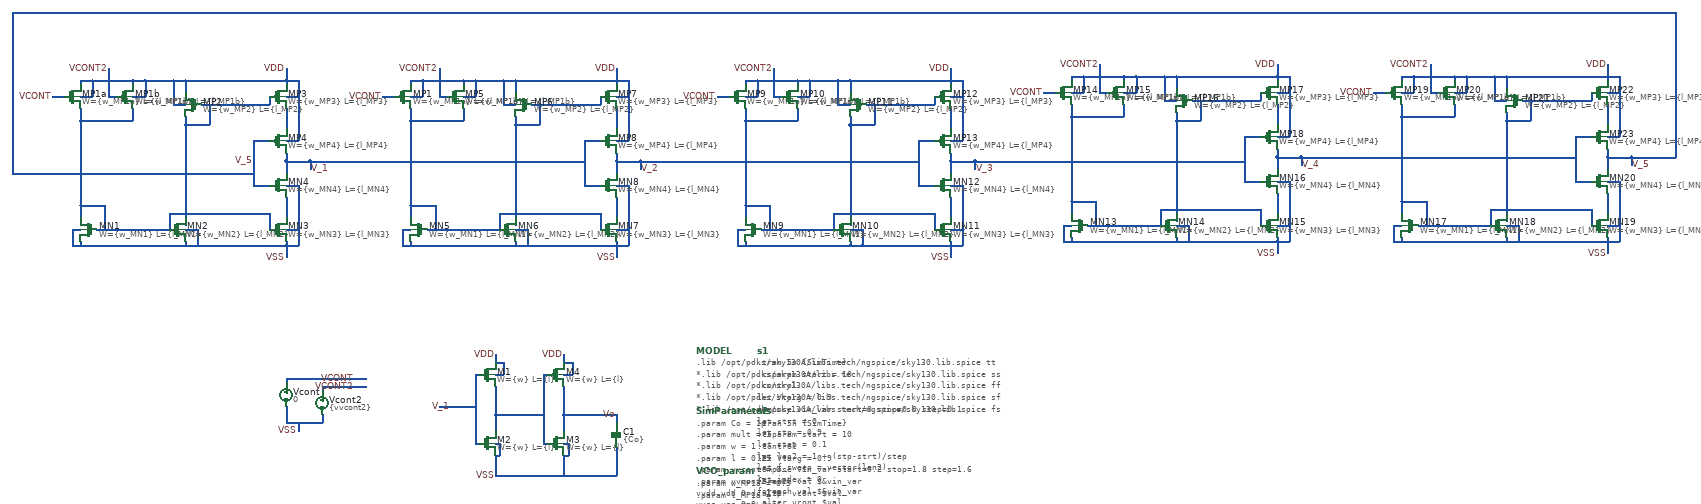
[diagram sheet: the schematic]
v {xschem version=3.4.5 file_version=1.2
}
G {}
K {}
V {}
S {}
E {}
N -2160 -960 -2160 -930 {
lab=VDD}
N -2160 -520 -2160 -490 {
lab=VSS}
N -1990 -190 -1960 -190 {
lab=VCONT}
N -1780 -120 -1750 -120 {
lab=V_1}
N -1640 -100 -1640 -60 {
lab=#net1}
N -1640 -170 -1640 -100 {
lab=#net1}
N -1640 -30 -1630 -30 {
lab=VSS}
N -1630 -30 -1630 0 {
lab=VSS}
N -1640 0 -1630 0 {
lab=VSS}
N -1640 -200 -1620 -200 {
lab=VDD}
N -1620 -230 -1620 -200 {
lab=VDD}
N -1640 -230 -1620 -230 {
lab=VDD}
N -1640 -100 -1630 -100 {
lab=#net1}
N -1690 -200 -1680 -200 {
lab=V_1}
N -1690 -200 -1690 -30 {
lab=V_1}
N -1690 -30 -1680 -30 {
lab=V_1}
N -1640 0 -1640 50 {
lab=VSS}
N -1640 -250 -1640 -230 {
lab=VDD}
N -1340 -20 -1340 50 {
lab=VSS}
N -1750 -120 -1720 -120 {
lab=V_1}
N -1340 -100 -1340 -80 {
lab=Vo}
N -1720 -120 -1690 -120 {
lab=V_1}
N -1470 -100 -1470 -60 {
lab=Vo}
N -1470 -170 -1470 -100 {
lab=Vo}
N -1470 -30 -1460 -30 {
lab=VSS}
N -1460 -30 -1460 0 {
lab=VSS}
N -1470 0 -1460 0 {
lab=VSS}
N -1470 -200 -1450 -200 {
lab=VDD}
N -1450 -230 -1450 -200 {
lab=VDD}
N -1470 -230 -1450 -230 {
lab=VDD}
N -1470 -100 -1460 -100 {
lab=Vo}
N -1520 -200 -1510 -200 {
lab=#net1}
N -1520 -200 -1520 -30 {
lab=#net1}
N -1520 -30 -1510 -30 {
lab=#net1}
N -1470 0 -1470 50 {
lab=VSS}
N -1470 -250 -1470 -230 {
lab=VDD}
N -1630 -100 -1520 -100 {
lab=#net1}
N -1470 -100 -1340 -100 {
lab=Vo}
N -1640 50 -1340 50 {
lab=VSS}
N -1990 -170 -1960 -170 {
lab=VCONT2}
N -2160 -190 -1990 -190 {
lab=VCONT}
N -2160 -190 -2160 -180 {
lab=VCONT}
N -2070 -170 -1990 -170 {
lab=VCONT2}
N -2070 -170 -2070 -160 {
lab=VCONT2}
N -2070 -100 -2070 -80 {
lab=VSS}
N -2160 -80 -2070 -80 {
lab=VSS}
N -2160 -120 -2160 -80 {
lab=VSS}
N -2130 -80 -2130 -60 {
lab=VSS}
N -2240 -780 -2200 -780 { lab=V_5}
N -2240 -780 -2240 -670 { lab=V_5}
N -2240 -670 -2200 -670 { lab=V_5}
N -2160 -730 -2160 -700 { lab=V_1}
N -2160 -860 -2160 -810 { lab=#net2}
N -2160 -780 -2130 -780 { lab=VDD}
N -2160 -670 -2130 -670 { lab=VSS}
N -2130 -670 -2130 -560 { lab=VSS}
N -2160 -640 -2160 -590 { lab=#net3}
N -2160 -730 -2100 -730 { lab=V_1}
N -2160 -520 -2160 -510 {
lab=VSS}
N -2160 -930 -2160 -920 {
lab=VDD}
N -2160 -930 -2130 -930 {
lab=VDD}
N -2130 -890 -2130 -780 {
lab=VDD}
N -2160 -890 -2130 -890 {
lab=VDD}
N -2160 -520 -2130 -520 {
lab=VSS}
N -2130 -560 -2130 -520 {
lab=VSS}
N -2160 -560 -2130 -560 {
lab=VSS}
N -2350 -870 -2200 -870 {
lab=#net4}
N -2410 -910 -2410 -900 {
lab=VDD}
N -2410 -930 -2160 -930 {
lab=VDD}
N -2410 -820 -2410 -570 {
lab=#net4}
N -2380 -520 -2160 -520 {
lab=VSS}
N -2410 -530 -2410 -520 {
lab=VSS}
N -2610 -560 -2450 -560 {
lab=#net5}
N -2670 -520 -2410 -520 {
lab=VSS}
N -2670 -530 -2670 -520 {
lab=VSS}
N -2670 -620 -2670 -590 {
lab=#net5}
N -2440 -930 -2410 -930 {
lab=VDD}
N -2670 -930 -2670 -920 {
lab=VDD}
N -2610 -620 -2610 -560 {
lab=#net5}
N -2670 -620 -2610 -620 {
lab=#net5}
N -2410 -820 -2350 -820 {
lab=#net4}
N -2350 -870 -2350 -820 {
lab=#net4}
N -2740 -890 -2710 -890 {
lab=VCONT}
N -2410 -560 -2380 -560 {
lab=VSS}
N -2380 -560 -2380 -520 {
lab=VSS}
N -2450 -600 -2450 -560 {
lab=#net5}
N -2450 -600 -2200 -600 {
lab=#net5}
N -2200 -600 -2200 -560 {
lab=#net5}
N -2690 -560 -2670 -560 {
lab=VSS}
N -2690 -560 -2690 -520 {
lab=VSS}
N -2690 -520 -2670 -520 {
lab=VSS}
N -2670 -890 -2640 -890 {
lab=VDD}
N -2640 -930 -2640 -890 {
lab=VDD}
N -2440 -870 -2410 -870 {
lab=VDD}
N -2440 -910 -2440 -870 {
lab=VDD}
N -2160 -750 -2160 -730 { lab=V_1}
N -2160 -940 -2160 -930 {
lab=VDD}
N -2130 -930 -2130 -890 {
lab=VDD}
N -2160 -530 -2160 -520 {
lab=VSS}
N -2630 -560 -2610 -560 {
lab=#net5}
N -2670 -830 -2670 -620 {
lab=#net5}
N -2410 -840 -2410 -820 {
lab=#net4}
N -2370 -870 -2350 -870 {
lab=#net4}
N -2410 -520 -2380 -520 {
lab=VSS}
N -2670 -930 -2640 -930 {
lab=VDD}
N -2510 -930 -2440 -930 {
lab=VDD}
N -2540 -930 -2540 -920 {
lab=VDD}
N -2540 -890 -2510 -890 {
lab=VDD}
N -2510 -930 -2510 -890 {
lab=VDD}
N -2540 -930 -2510 -930 {
lab=VDD}
N -2640 -930 -2540 -930 {
lab=VDD}
N -2540 -860 -2540 -830 {
lab=#net5}
N -2670 -830 -2540 -830 {
lab=#net5}
N -2670 -860 -2670 -830 {
lab=#net5}
N -2600 -890 -2580 -890 {
lab=VCONT2}
N -2200 -890 -2200 -870 {
lab=#net4}
N -2440 -930 -2440 -910 {
lab=VDD}
N -2410 -930 -2410 -910 {
lab=VDD}
N -2600 -960 -2600 -890 {
lab=VCONT2}
N -1340 -960 -1340 -930 {
lab=VDD}
N -1340 -520 -1340 -490 {
lab=VSS}
N -1420 -780 -1380 -780 { lab=V_1}
N -1420 -780 -1420 -670 { lab=V_1}
N -1420 -670 -1380 -670 { lab=V_1}
N -1340 -730 -1340 -700 { lab=V_2}
N -1340 -860 -1340 -810 { lab=#net6}
N -1340 -780 -1310 -780 { lab=VDD}
N -1340 -670 -1310 -670 { lab=VSS}
N -1310 -670 -1310 -560 { lab=VSS}
N -1340 -640 -1340 -590 { lab=#net7}
N -1340 -730 -1280 -730 { lab=V_2}
N -1340 -520 -1340 -510 {
lab=VSS}
N -1340 -930 -1340 -920 {
lab=VDD}
N -1340 -930 -1310 -930 {
lab=VDD}
N -1310 -890 -1310 -780 {
lab=VDD}
N -1340 -890 -1310 -890 {
lab=VDD}
N -1340 -520 -1310 -520 {
lab=VSS}
N -1310 -560 -1310 -520 {
lab=VSS}
N -1340 -560 -1310 -560 {
lab=VSS}
N -1530 -870 -1380 -870 {
lab=#net8}
N -1590 -910 -1590 -900 {
lab=VDD}
N -1590 -930 -1340 -930 {
lab=VDD}
N -1590 -820 -1590 -570 {
lab=#net8}
N -1560 -520 -1340 -520 {
lab=VSS}
N -1590 -530 -1590 -520 {
lab=VSS}
N -1790 -560 -1630 -560 {
lab=#net9}
N -1850 -520 -1590 -520 {
lab=VSS}
N -1850 -530 -1850 -520 {
lab=VSS}
N -1850 -620 -1850 -590 {
lab=#net9}
N -1620 -930 -1590 -930 {
lab=VDD}
N -1850 -930 -1850 -920 {
lab=VDD}
N -1790 -620 -1790 -560 {
lab=#net9}
N -1850 -620 -1790 -620 {
lab=#net9}
N -1590 -820 -1530 -820 {
lab=#net8}
N -1530 -870 -1530 -820 {
lab=#net8}
N -1920 -890 -1890 -890 {
lab=VCONT}
N -1590 -560 -1560 -560 {
lab=VSS}
N -1560 -560 -1560 -520 {
lab=VSS}
N -1630 -600 -1630 -560 {
lab=#net9}
N -1630 -600 -1380 -600 {
lab=#net9}
N -1380 -600 -1380 -560 {
lab=#net9}
N -1870 -560 -1850 -560 {
lab=VSS}
N -1870 -560 -1870 -520 {
lab=VSS}
N -1870 -520 -1850 -520 {
lab=VSS}
N -1850 -890 -1820 -890 {
lab=VDD}
N -1820 -930 -1820 -890 {
lab=VDD}
N -1620 -870 -1590 -870 {
lab=VDD}
N -1620 -910 -1620 -870 {
lab=VDD}
N -1340 -750 -1340 -730 { lab=V_2}
N -1340 -940 -1340 -930 {
lab=VDD}
N -1310 -930 -1310 -890 {
lab=VDD}
N -1340 -530 -1340 -520 {
lab=VSS}
N -1810 -560 -1790 -560 {
lab=#net9}
N -1850 -830 -1850 -620 {
lab=#net9}
N -1590 -840 -1590 -820 {
lab=#net8}
N -1550 -870 -1530 -870 {
lab=#net8}
N -1590 -520 -1560 -520 {
lab=VSS}
N -1850 -930 -1820 -930 {
lab=VDD}
N -1690 -930 -1620 -930 {
lab=VDD}
N -1720 -930 -1720 -920 {
lab=VDD}
N -1720 -890 -1690 -890 {
lab=VDD}
N -1690 -930 -1690 -890 {
lab=VDD}
N -1720 -930 -1690 -930 {
lab=VDD}
N -1820 -930 -1720 -930 {
lab=VDD}
N -1720 -860 -1720 -830 {
lab=#net9}
N -1850 -830 -1720 -830 {
lab=#net9}
N -1850 -860 -1850 -830 {
lab=#net9}
N -1780 -890 -1760 -890 {
lab=VCONT2}
N -1380 -890 -1380 -870 {
lab=#net8}
N -1620 -930 -1620 -910 {
lab=VDD}
N -1590 -930 -1590 -910 {
lab=VDD}
N -1780 -960 -1780 -890 {
lab=VCONT2}
N -510 -960 -510 -930 {
lab=VDD}
N -510 -520 -510 -490 {
lab=VSS}
N -590 -780 -550 -780 { lab=V_2}
N -590 -780 -590 -670 { lab=V_2}
N -590 -670 -550 -670 { lab=V_2}
N -510 -730 -510 -700 { lab=V_3}
N -510 -860 -510 -810 { lab=#net10}
N -510 -780 -480 -780 { lab=VDD}
N -510 -670 -480 -670 { lab=VSS}
N -480 -670 -480 -560 { lab=VSS}
N -510 -640 -510 -590 { lab=#net11}
N -510 -730 -450 -730 { lab=V_3}
N -510 -520 -510 -510 {
lab=VSS}
N -510 -930 -510 -920 {
lab=VDD}
N -510 -930 -480 -930 {
lab=VDD}
N -480 -890 -480 -780 {
lab=VDD}
N -510 -890 -480 -890 {
lab=VDD}
N -510 -520 -480 -520 {
lab=VSS}
N -480 -560 -480 -520 {
lab=VSS}
N -510 -560 -480 -560 {
lab=VSS}
N -700 -870 -550 -870 {
lab=#net12}
N -760 -910 -760 -900 {
lab=VDD}
N -760 -930 -510 -930 {
lab=VDD}
N -760 -820 -760 -570 {
lab=#net12}
N -730 -520 -510 -520 {
lab=VSS}
N -760 -530 -760 -520 {
lab=VSS}
N -960 -560 -800 -560 {
lab=#net13}
N -1020 -520 -760 -520 {
lab=VSS}
N -1020 -530 -1020 -520 {
lab=VSS}
N -1020 -620 -1020 -590 {
lab=#net13}
N -790 -930 -760 -930 {
lab=VDD}
N -1020 -930 -1020 -920 {
lab=VDD}
N -960 -620 -960 -560 {
lab=#net13}
N -1020 -620 -960 -620 {
lab=#net13}
N -760 -820 -700 -820 {
lab=#net12}
N -700 -870 -700 -820 {
lab=#net12}
N -1090 -890 -1060 -890 {
lab=VCONT}
N -760 -560 -730 -560 {
lab=VSS}
N -730 -560 -730 -520 {
lab=VSS}
N -800 -600 -800 -560 {
lab=#net13}
N -800 -600 -550 -600 {
lab=#net13}
N -550 -600 -550 -560 {
lab=#net13}
N -1040 -560 -1020 -560 {
lab=VSS}
N -1040 -560 -1040 -520 {
lab=VSS}
N -1040 -520 -1020 -520 {
lab=VSS}
N -1020 -890 -990 -890 {
lab=VDD}
N -990 -930 -990 -890 {
lab=VDD}
N -790 -870 -760 -870 {
lab=VDD}
N -790 -910 -790 -870 {
lab=VDD}
N -510 -750 -510 -730 { lab=V_3}
N -510 -940 -510 -930 {
lab=VDD}
N -480 -930 -480 -890 {
lab=VDD}
N -510 -530 -510 -520 {
lab=VSS}
N -980 -560 -960 -560 {
lab=#net13}
N -1020 -830 -1020 -620 {
lab=#net13}
N -760 -840 -760 -820 {
lab=#net12}
N -720 -870 -700 -870 {
lab=#net12}
N -760 -520 -730 -520 {
lab=VSS}
N -1020 -930 -990 -930 {
lab=VDD}
N -860 -930 -790 -930 {
lab=VDD}
N -890 -930 -890 -920 {
lab=VDD}
N -890 -890 -860 -890 {
lab=VDD}
N -860 -930 -860 -890 {
lab=VDD}
N -890 -930 -860 -930 {
lab=VDD}
N -990 -930 -890 -930 {
lab=VDD}
N -890 -860 -890 -830 {
lab=#net13}
N -1020 -830 -890 -830 {
lab=#net13}
N -1020 -860 -1020 -830 {
lab=#net13}
N -950 -890 -930 -890 {
lab=VCONT2}
N -550 -890 -550 -870 {
lab=#net12}
N -790 -930 -790 -910 {
lab=VDD}
N -760 -930 -760 -910 {
lab=VDD}
N -950 -960 -950 -890 {
lab=VCONT2}
N 300 -970 300 -940 {
lab=VDD}
N 300 -530 300 -500 {
lab=VSS}
N 220 -790 260 -790 { lab=V_3}
N 220 -790 220 -680 { lab=V_3}
N 220 -680 260 -680 { lab=V_3}
N 300 -740 300 -710 { lab=V_4}
N 300 -870 300 -820 { lab=#net14}
N 300 -790 330 -790 { lab=VDD}
N 300 -680 330 -680 { lab=VSS}
N 330 -680 330 -570 { lab=VSS}
N 300 -650 300 -600 { lab=#net15}
N 300 -740 360 -740 { lab=V_4}
N 300 -530 300 -520 {
lab=VSS}
N 300 -940 300 -930 {
lab=VDD}
N 300 -940 330 -940 {
lab=VDD}
N 330 -900 330 -790 {
lab=VDD}
N 300 -900 330 -900 {
lab=VDD}
N 300 -530 330 -530 {
lab=VSS}
N 330 -570 330 -530 {
lab=VSS}
N 300 -570 330 -570 {
lab=VSS}
N 110 -880 260 -880 {
lab=#net16}
N 50 -920 50 -910 {
lab=VDD}
N 50 -940 300 -940 {
lab=VDD}
N 50 -830 50 -580 {
lab=#net16}
N 80 -530 300 -530 {
lab=VSS}
N 50 -540 50 -530 {
lab=VSS}
N -150 -570 10 -570 {
lab=#net17}
N -210 -530 50 -530 {
lab=VSS}
N -210 -540 -210 -530 {
lab=VSS}
N -210 -630 -210 -600 {
lab=#net17}
N 20 -940 50 -940 {
lab=VDD}
N -210 -940 -210 -930 {
lab=VDD}
N -150 -630 -150 -570 {
lab=#net17}
N -210 -630 -150 -630 {
lab=#net17}
N 50 -830 110 -830 {
lab=#net16}
N 110 -880 110 -830 {
lab=#net16}
N -280 -900 -250 -900 {
lab=VCONT}
N 50 -570 80 -570 {
lab=VSS}
N 80 -570 80 -530 {
lab=VSS}
N 10 -610 10 -570 {
lab=#net17}
N 10 -610 260 -610 {
lab=#net17}
N 260 -610 260 -570 {
lab=#net17}
N -230 -570 -210 -570 {
lab=VSS}
N -230 -570 -230 -530 {
lab=VSS}
N -230 -530 -210 -530 {
lab=VSS}
N -210 -900 -180 -900 {
lab=VDD}
N -180 -940 -180 -900 {
lab=VDD}
N 20 -880 50 -880 {
lab=VDD}
N 20 -920 20 -880 {
lab=VDD}
N 300 -760 300 -740 { lab=V_4}
N 300 -950 300 -940 {
lab=VDD}
N 330 -940 330 -900 {
lab=VDD}
N 300 -540 300 -530 {
lab=VSS}
N -170 -570 -150 -570 {
lab=#net17}
N -210 -840 -210 -630 {
lab=#net17}
N 50 -850 50 -830 {
lab=#net16}
N 90 -880 110 -880 {
lab=#net16}
N 50 -530 80 -530 {
lab=VSS}
N -210 -940 -180 -940 {
lab=VDD}
N -50 -940 20 -940 {
lab=VDD}
N -80 -940 -80 -930 {
lab=VDD}
N -80 -900 -50 -900 {
lab=VDD}
N -50 -940 -50 -900 {
lab=VDD}
N -80 -940 -50 -940 {
lab=VDD}
N -180 -940 -80 -940 {
lab=VDD}
N -80 -870 -80 -840 {
lab=#net17}
N -210 -840 -80 -840 {
lab=#net17}
N -210 -870 -210 -840 {
lab=#net17}
N -140 -900 -120 -900 {
lab=VCONT2}
N 260 -900 260 -880 {
lab=#net16}
N 20 -940 20 -920 {
lab=VDD}
N 50 -940 50 -920 {
lab=VDD}
N -140 -970 -140 -900 {
lab=VCONT2}
N 1120 -970 1120 -940 {
lab=VDD}
N 1120 -530 1120 -500 {
lab=VSS}
N 1040 -790 1080 -790 { lab=V_4}
N 1040 -790 1040 -680 { lab=V_4}
N 1040 -680 1080 -680 { lab=V_4}
N 1120 -740 1120 -710 { lab=V_5}
N 1120 -870 1120 -820 { lab=#net18}
N 1120 -790 1150 -790 { lab=VDD}
N 1120 -680 1150 -680 { lab=VSS}
N 1150 -680 1150 -570 { lab=VSS}
N 1120 -650 1120 -600 { lab=#net19}
N 1120 -740 1180 -740 { lab=V_5}
N 1120 -530 1120 -520 {
lab=VSS}
N 1120 -940 1120 -930 {
lab=VDD}
N 1120 -940 1150 -940 {
lab=VDD}
N 1150 -900 1150 -790 {
lab=VDD}
N 1120 -900 1150 -900 {
lab=VDD}
N 1120 -530 1150 -530 {
lab=VSS}
N 1150 -570 1150 -530 {
lab=VSS}
N 1120 -570 1150 -570 {
lab=VSS}
N 930 -880 1080 -880 {
lab=#net20}
N 870 -920 870 -910 {
lab=VDD}
N 870 -940 1120 -940 {
lab=VDD}
N 870 -830 870 -580 {
lab=#net20}
N 900 -530 1120 -530 {
lab=VSS}
N 870 -540 870 -530 {
lab=VSS}
N 670 -570 830 -570 {
lab=#net21}
N 610 -530 870 -530 {
lab=VSS}
N 610 -540 610 -530 {
lab=VSS}
N 610 -630 610 -600 {
lab=#net21}
N 840 -940 870 -940 {
lab=VDD}
N 610 -940 610 -930 {
lab=VDD}
N 670 -630 670 -570 {
lab=#net21}
N 610 -630 670 -630 {
lab=#net21}
N 870 -830 930 -830 {
lab=#net20}
N 930 -880 930 -830 {
lab=#net20}
N 540 -900 570 -900 {
lab=VCONT}
N 870 -570 900 -570 {
lab=VSS}
N 900 -570 900 -530 {
lab=VSS}
N 830 -610 830 -570 {
lab=#net21}
N 830 -610 1080 -610 {
lab=#net21}
N 1080 -610 1080 -570 {
lab=#net21}
N 590 -570 610 -570 {
lab=VSS}
N 590 -570 590 -530 {
lab=VSS}
N 590 -530 610 -530 {
lab=VSS}
N 610 -900 640 -900 {
lab=VDD}
N 640 -940 640 -900 {
lab=VDD}
N 840 -880 870 -880 {
lab=VDD}
N 840 -920 840 -880 {
lab=VDD}
N 1120 -760 1120 -740 { lab=V_5}
N 1120 -950 1120 -940 {
lab=VDD}
N 1150 -940 1150 -900 {
lab=VDD}
N 1120 -540 1120 -530 {
lab=VSS}
N 650 -570 670 -570 {
lab=#net21}
N 610 -840 610 -630 {
lab=#net21}
N 870 -850 870 -830 {
lab=#net20}
N 910 -880 930 -880 {
lab=#net20}
N 870 -530 900 -530 {
lab=VSS}
N 610 -940 640 -940 {
lab=VDD}
N 770 -940 840 -940 {
lab=VDD}
N 740 -940 740 -930 {
lab=VDD}
N 740 -900 770 -900 {
lab=VDD}
N 770 -940 770 -900 {
lab=VDD}
N 740 -940 770 -940 {
lab=VDD}
N 640 -940 740 -940 {
lab=VDD}
N 740 -870 740 -840 {
lab=#net21}
N 610 -840 740 -840 {
lab=#net21}
N 610 -870 610 -840 {
lab=#net21}
N 680 -900 700 -900 {
lab=VCONT2}
N 1080 -900 1080 -880 {
lab=#net20}
N 840 -940 840 -920 {
lab=VDD}
N 870 -940 870 -920 {
lab=VDD}
N 680 -970 680 -900 {
lab=VCONT2}
N -2100 -730 -2100 -710 {
lab=V_1}
N -2100 -730 -1420 -730 {
lab=V_1}
N -1280 -730 -1280 -710 {
lab=V_2}
N -1280 -730 -590 -730 {
lab=V_2}
N -450 -730 -450 -710 {
lab=V_3}
N -450 -730 220 -730 {
lab=V_3}
N 360 -740 360 -720 {
lab=V_4}
N 360 -740 1040 -740 {
lab=V_4}
N 1180 -740 1180 -720 {
lab=V_5}
N 1180 -740 1290 -740 {
lab=V_5}
N 1290 -1100 1290 -740 {
lab=V_5}
N -2840 -1100 1290 -1100 {
lab=V_5}
N -2840 -1100 -2840 -700 {
lab=V_5}
N -2840 -700 -2240 -700 {
lab=V_5}
C {code.sym} -1140 -260 0 0 {name=MODEL only_toplevel=true spice_ignore=false
format="tcleval( @value )"
value="
.lib /opt/pdks/sky130A/libs.tech/ngspice/sky130.lib.spice tt
*.lib /opt/pdks/sky130A/libs.tech/ngspice/sky130.lib.spice ss
*.lib /opt/pdks/sky130A/libs.tech/ngspice/sky130.lib.spice ff
*.lib /opt/pdks/sky130A/libs.tech/ngspice/sky130.lib.spice sf
*.lib /opt/pdks/sky130A/libs.tech/ngspice/sky130.lib.spice fs
"}
C {code.sym} -1140 -110 0 0 {name=SimParameters only_toplevel=true spice_ignore=false
format="tcleval( @value )"
value="
.param Co = 1p
.param mult = 1
.param w = 1
.param l = 0.15

.param vvcont = 0
.param vvcont2 = 0

vvdd vdd 0 dc 1.8
vvss vss 0 0
*vvcont VCONT 0 dc 0
*vvcont2 VCONT2 0 dc 0
*.option temp = 200
.ic v(V_1) = 0
.ic v(V_2) = 1.8
.save v(V_1) v(Vo)

.param SimTime =  40u
.csparam SimTime =\{Simtime\}
.csparam Tmargin = 10u


"}
C {devices/code.sym} -990 -260 0 0 {name=s1 only_toplevel=false spice_ignore=false
value="

.tran 5n \{SimTime\}
.csparam start = 10
.control
let Vtarg = 0.9
compose vin_var start=0 stop=0.9 step=0.1

let strt = 0
let stp = 0.9
let step = 0.1
let len2 = 1 + (stp-strt)/step
let f_sweep = vector(len2)
let index = 0
foreach val $&vin_var
	alter vcont $val
	let f_sum = 0
	let t_act = 0
	let period_cont = 1
	let period_cont2 = 2
	run
	while t_act le SimTime - Tmargin
		meas tran t_rise WHEN v(Vo) = \{Vtarg\} RISE = \{period_cont\}
		let t_act = t_rise
		*print t_act SimTime period_cont
		meas tran T TRIG v(Vo) VAL = \{Vtarg\} RISE = \{period_cont\} TARG v(Vo) VAL = \{Vtarg\}  RISE = \{period_cont2\}
		let f =1/T
		let f_sum = f_sum + f
		let period_cont = period_cont + 1
		let period_cont2 = period_cont2 + 1
	end
	*wrdata ../../sim_data/data_VCO_vto1p1.txt tran1.v(V_1) tran2.v(V_1) tran3.v(V_1) tran4.v(V_1) tran5.v(V_1) tran6.v(V_1) tran7.v(V_1) tran8.v(V_1) tran9.v(V_1) tran10.v(V_1) tran11.v(V_1) tran12.v(V_1) tran13.v(V_1) tran14.v(V_1) tran15.v(V_1) tran16.v(V_1) tran17.v(V_1)
	let f_avg = f_sum/(period_cont-1)
	let f_sweep[index] = f_avg
	let index = index +1
end
plot tran1.v(Vo) 
plot tran9.v(Vo)
print f_sweep
plot f_sweep vs vin_var
.endc
"}
C {devices/code.sym} -990 -110 0 0 {name=s2 only_toplevel=false spice_ignore=true
value="

.tran 5n \{SimTime\}
.csparam start = 10
.control
let Vtarg = 0.9
compose vin_var start=0.2 stop=1.8 step=1.6
foreach val $&vin_var
	alter vcont $val
	run
end
plot tran1.v(Vo) 
plot tran2.v(Vo)
*print f_sweep
*plot f_sweep vs vin_var
.endc
"}
C {code.sym} -1140 40 0 0 {name=VCO_param only_toplevel=true spice_ignore=false
format="tcleval( @value )"
value="

.param w_MP1a = 0.5
.param l_MP1a = 7
.param w_MP1b = 4
.param l_MP1b = 7
.param w_MP2 = 8
.param l_MP2 = 4
.param w_MP3 = 5
.param l_MP3 = 4
.param w_MP4 = 5
.param l_MP4 = 5

.param w_MN1 = 5
.param l_MN1 = 0.5
.param w_MN2 = 5
.param l_MN2 = 0.5
.param w_MN3 = 3
.param l_MN3 = 0.5
.param w_MN4 = 2
.param l_MN4 = 5


"}
C {devices/lab_pin.sym} -2160 -960 1 0 {name=p4 sig_type=std_logic lab=VDD}
C {devices/lab_pin.sym} -2160 -490 3 0 {name=p5 sig_type=std_logic lab=VSS}
C {devices/lab_pin.sym} -1990 -190 1 0 {name=p6 sig_type=std_logic lab=VCONT}
C {devices/lab_pin.sym} -1750 -120 1 0 {name=p7 sig_type=std_logic lab=V_1}
C {sky130_fd_pr/nfet_01v8.sym} -1660 -30 0 0 {name=M2
W=\{w\}
L=\{l\}
nf=1
mult=\{mult\}
ad="'int((nf+1)/2) * W/nf * 0.29'" 
pd="'2*int((nf+1)/2) * (W/nf + 0.29)'"
as="'int((nf+2)/2) * W/nf * 0.29'" 
ps="'2*int((nf+2)/2) * (W/nf + 0.29)'"
nrd="'0.29 / W'" nrs="'0.29 / W'"
sa=0 sb=0 sd=0
model=nfet_01v8
spiceprefix=X
}
C {sky130_fd_pr/pfet_01v8.sym} -1660 -200 0 0 {name=M1
W=\{w\}
L=\{l\}
nf=1
mult=\{mult*3\}
ad="'int((nf+1)/2) * W/nf * 0.29'" 
pd="'2*int((nf+1)/2) * (W/nf + 0.29)'"
as="'int((nf+2)/2) * W/nf * 0.29'" 
ps="'2*int((nf+2)/2) * (W/nf + 0.29)'"
nrd="'0.29 / W'" nrs="'0.29 / W'"
sa=0 sb=0 sd=0
model=pfet_01v8
spiceprefix=X
}
C {devices/lab_pin.sym} -1470 -250 1 0 {name=p2 sig_type=std_logic lab=VDD}
C {devices/lab_pin.sym} -1640 50 3 0 {name=p3 sig_type=std_logic lab=VSS}
C {devices/lab_pin.sym} -1340 -100 1 0 {name=p8 sig_type=std_logic lab=Vo}
C {capa.sym} -1340 -50 0 0 {name=C1
m=1
value=\{Co\}
footprint=1206
device="ceramic capacitor"}
C {sky130_fd_pr/nfet_01v8.sym} -1490 -30 0 0 {name=M3
W=\{w\}
L=\{l\}
nf=1
mult=\{mult\}
ad="'int((nf+1)/2) * W/nf * 0.29'" 
pd="'2*int((nf+1)/2) * (W/nf + 0.29)'"
as="'int((nf+2)/2) * W/nf * 0.29'" 
ps="'2*int((nf+2)/2) * (W/nf + 0.29)'"
nrd="'0.29 / W'" nrs="'0.29 / W'"
sa=0 sb=0 sd=0
model=nfet_01v8
spiceprefix=X
}
C {sky130_fd_pr/pfet_01v8.sym} -1490 -200 0 0 {name=M4
W=\{w\}
L=\{l\}
nf=1
mult=\{mult*3\}
ad="'int((nf+1)/2) * W/nf * 0.29'" 
pd="'2*int((nf+1)/2) * (W/nf + 0.29)'"
as="'int((nf+2)/2) * W/nf * 0.29'" 
ps="'2*int((nf+2)/2) * (W/nf + 0.29)'"
nrd="'0.29 / W'" nrs="'0.29 / W'"
sa=0 sb=0 sd=0
model=pfet_01v8
spiceprefix=X
}
C {devices/lab_pin.sym} -1640 -250 1 0 {name=p9 sig_type=std_logic lab=VDD}
C {devices/lab_pin.sym} -1990 -170 1 1 {name=p10 sig_type=std_logic lab=VCONT2}
C {vsource.sym} -2160 -150 0 0 {name=Vcont value=0 savecurrent=false}
C {devices/lab_pin.sym} -2130 -60 3 0 {name=p11 sig_type=std_logic lab=VSS}
C {vsource.sym} -2070 -130 0 0 {name=Vcont2 value=\{vvcont2\} savecurrent=false}
C {sky130_fd_pr/pfet_01v8.sym} -2690 -890 0 0 {name=MP1a
W= \{w_MP1a\}
L= \{l_MP1a\}
nf=1
mult=1
ad="'int((nf+1)/2) * W/nf * 0.29'" 
pd="'2*int((nf+1)/2) * (W/nf + 0.29)'"
as="'int((nf+2)/2) * W/nf * 0.29'" 
ps="'2*int((nf+2)/2) * (W/nf + 0.29)'"
nrd="'0.29 / W'" nrs="'0.29 / W'"
sa=0 sb=0 sd=0
model=pfet_01v8
spiceprefix=X
}
C {sky130_fd_pr/pfet_01v8.sym} -2560 -890 0 0 {name=MP1b
W=\{w_MP1b\}
*W=7
L=\{l_MP1b\}
nf=1
mult=1
ad="'int((nf+1)/2) * W/nf * 0.29'" 
pd="'2*int((nf+1)/2) * (W/nf + 0.29)'"
as="'int((nf+2)/2) * W/nf * 0.29'" 
ps="'2*int((nf+2)/2) * (W/nf + 0.29)'"
nrd="'0.29 / W'" nrs="'0.29 / W'"
sa=0 sb=0 sd=0
model=pfet_01v8
spiceprefix=X
}
C {sky130_fd_pr/pfet_01v8.sym} -2390 -870 0 1 {name=MP2
*W= 8
W = \{w_MP2\}
*L= 4
L = \{l_MP2\}
nf=1
mult=1
ad="'int((nf+1)/2) * W/nf * 0.29'" 
pd="'2*int((nf+1)/2) * (W/nf + 0.29)'"
as="'int((nf+2)/2) * W/nf * 0.29'" 
ps="'2*int((nf+2)/2) * (W/nf + 0.29)'"
nrd="'0.29 / W'" nrs="'0.29 / W'"
sa=0 sb=0 sd=0
model=pfet_01v8
spiceprefix=X
}
C {sky130_fd_pr/pfet_01v8.sym} -2180 -890 0 0 {name=MP3
*W=5
W = \{w_MP3\}
*L=4
L = \{l_MP3\}
nf=1
mult=1
ad="'int((nf+1)/2) * W/nf * 0.29'" 
pd="'2*int((nf+1)/2) * (W/nf + 0.29)'"
as="'int((nf+2)/2) * W/nf * 0.29'" 
ps="'2*int((nf+2)/2) * (W/nf + 0.29)'"
nrd="'0.29 / W'" nrs="'0.29 / W'"
sa=0 sb=0 sd=0
model=pfet_01v8
spiceprefix=X
}
C {sky130_fd_pr/pfet_01v8.sym} -2180 -780 0 0 {name=MP4
*W=5
W = \{w_MP4\}
L = \{l_MP4\}
*L=5
nf=1
mult=1
ad="'int((nf+1)/2) * W/nf * 0.29'" 
pd="'2*int((nf+1)/2) * (W/nf + 0.29)'"
as="'int((nf+2)/2) * W/nf * 0.29'" 
ps="'2*int((nf+2)/2) * (W/nf + 0.29)'"
nrd="'0.29 / W'" nrs="'0.29 / W'"
sa=0 sb=0 sd=0
model=pfet_01v8
spiceprefix=X
}
C {sky130_fd_pr/nfet_01v8.sym} -2650 -560 0 1 {name=MN1
*W=5
W = \{w_MN1\}
*L=0.5
L = \{l_MN1\}
nf=1
mult=1
ad="'int((nf+1)/2) * W/nf * 0.29'" 
pd="'2*int((nf+1)/2) * (W/nf + 0.29)'"
as="'int((nf+2)/2) * W/nf * 0.29'" 
ps="'2*int((nf+2)/2) * (W/nf + 0.29)'"
nrd="'0.29 / W'" nrs="'0.29 / W'"
sa=0 sb=0 sd=0
model=nfet_01v8
spiceprefix=X
}
C {sky130_fd_pr/nfet_01v8.sym} -2430 -560 0 0 {name=MN2
*W=5
W = \{w_MN2\}
*L=0.5
L = \{l_MN2\}
nf=1
mult=1
ad="'int((nf+1)/2) * W/nf * 0.29'" 
pd="'2*int((nf+1)/2) * (W/nf + 0.29)'"
as="'int((nf+2)/2) * W/nf * 0.29'" 
ps="'2*int((nf+2)/2) * (W/nf + 0.29)'"
nrd="'0.29 / W'" nrs="'0.29 / W'"
sa=0 sb=0 sd=0
model=nfet_01v8
spiceprefix=X
}
C {sky130_fd_pr/nfet_01v8.sym} -2180 -560 0 0 {name=MN3
*W=3
W = \{w_MN3\}
*L=0.5
L = \{l_MN3\}
nf=1
mult=1
ad="'int((nf+1)/2) * W/nf * 0.29'" 
pd="'2*int((nf+1)/2) * (W/nf + 0.29)'"
as="'int((nf+2)/2) * W/nf * 0.29'" 
ps="'2*int((nf+2)/2) * (W/nf + 0.29)'"
nrd="'0.29 / W'" nrs="'0.29 / W'"
sa=0 sb=0 sd=0
model=nfet_01v8
spiceprefix=X
}
C {sky130_fd_pr/nfet_01v8.sym} -2180 -670 0 0 {name=MN4
*W=2
W = \{w_MN4\}
*L=5
L = \{l_MN4\}
nf=1
mult=1
ad="'int((nf+1)/2) * W/nf * 0.29'" 
pd="'2*int((nf+1)/2) * (W/nf + 0.29)'"
as="'int((nf+2)/2) * W/nf * 0.29'" 
ps="'2*int((nf+2)/2) * (W/nf + 0.29)'"
nrd="'0.29 / W'" nrs="'0.29 / W'"
sa=0 sb=0 sd=0
model=nfet_01v8
spiceprefix=X
}
C {devices/lab_pin.sym} -2740 -890 0 0 {name=p27 sig_type=std_logic lab=VCONT}
C {devices/lab_pin.sym} -2600 -960 2 1 {name=p28 sig_type=std_logic lab=VCONT2}
C {devices/lab_pin.sym} -2100 -710 2 0 {name=p21 sig_type=std_logic lab=V_1}
C {devices/lab_pin.sym} -2240 -730 0 0 {name=p22 sig_type=std_logic lab=V_5}
C {devices/lab_pin.sym} -1340 -960 1 0 {name=p23 sig_type=std_logic lab=VDD}
C {devices/lab_pin.sym} -1340 -490 3 0 {name=p24 sig_type=std_logic lab=VSS}
C {sky130_fd_pr/pfet_01v8.sym} -1870 -890 0 0 {name=MP1
W= \{w_MP1a\}
L= \{l_MP1a\}
nf=1
mult=1
ad="'int((nf+1)/2) * W/nf * 0.29'" 
pd="'2*int((nf+1)/2) * (W/nf + 0.29)'"
as="'int((nf+2)/2) * W/nf * 0.29'" 
ps="'2*int((nf+2)/2) * (W/nf + 0.29)'"
nrd="'0.29 / W'" nrs="'0.29 / W'"
sa=0 sb=0 sd=0
model=pfet_01v8
spiceprefix=X
}
C {sky130_fd_pr/pfet_01v8.sym} -1740 -890 0 0 {name=MP5
W=\{w_MP1b\}
*W=7
L=\{l_MP1b\}
nf=1
mult=1
ad="'int((nf+1)/2) * W/nf * 0.29'" 
pd="'2*int((nf+1)/2) * (W/nf + 0.29)'"
as="'int((nf+2)/2) * W/nf * 0.29'" 
ps="'2*int((nf+2)/2) * (W/nf + 0.29)'"
nrd="'0.29 / W'" nrs="'0.29 / W'"
sa=0 sb=0 sd=0
model=pfet_01v8
spiceprefix=X
}
C {sky130_fd_pr/pfet_01v8.sym} -1570 -870 0 1 {name=MP6
*W= 8
W = \{w_MP2\}
*L= 4
L = \{l_MP2\}
nf=1
mult=1
ad="'int((nf+1)/2) * W/nf * 0.29'" 
pd="'2*int((nf+1)/2) * (W/nf + 0.29)'"
as="'int((nf+2)/2) * W/nf * 0.29'" 
ps="'2*int((nf+2)/2) * (W/nf + 0.29)'"
nrd="'0.29 / W'" nrs="'0.29 / W'"
sa=0 sb=0 sd=0
model=pfet_01v8
spiceprefix=X
}
C {sky130_fd_pr/pfet_01v8.sym} -1360 -890 0 0 {name=MP7
*W=5
W = \{w_MP3\}
*L=4
L = \{l_MP3\}
nf=1
mult=1
ad="'int((nf+1)/2) * W/nf * 0.29'" 
pd="'2*int((nf+1)/2) * (W/nf + 0.29)'"
as="'int((nf+2)/2) * W/nf * 0.29'" 
ps="'2*int((nf+2)/2) * (W/nf + 0.29)'"
nrd="'0.29 / W'" nrs="'0.29 / W'"
sa=0 sb=0 sd=0
model=pfet_01v8
spiceprefix=X
}
C {sky130_fd_pr/pfet_01v8.sym} -1360 -780 0 0 {name=MP8
*W=5
W = \{w_MP4\}
L = \{l_MP4\}
*L=5
nf=1
mult=1
ad="'int((nf+1)/2) * W/nf * 0.29'" 
pd="'2*int((nf+1)/2) * (W/nf + 0.29)'"
as="'int((nf+2)/2) * W/nf * 0.29'" 
ps="'2*int((nf+2)/2) * (W/nf + 0.29)'"
nrd="'0.29 / W'" nrs="'0.29 / W'"
sa=0 sb=0 sd=0
model=pfet_01v8
spiceprefix=X
}
C {sky130_fd_pr/nfet_01v8.sym} -1830 -560 0 1 {name=MN5
*W=5
W = \{w_MN1\}
*L=0.5
L = \{l_MN1\}
nf=1
mult=1
ad="'int((nf+1)/2) * W/nf * 0.29'" 
pd="'2*int((nf+1)/2) * (W/nf + 0.29)'"
as="'int((nf+2)/2) * W/nf * 0.29'" 
ps="'2*int((nf+2)/2) * (W/nf + 0.29)'"
nrd="'0.29 / W'" nrs="'0.29 / W'"
sa=0 sb=0 sd=0
model=nfet_01v8
spiceprefix=X
}
C {sky130_fd_pr/nfet_01v8.sym} -1610 -560 0 0 {name=MN6
*W=5
W = \{w_MN2\}
*L=0.5
L = \{l_MN2\}
nf=1
mult=1
ad="'int((nf+1)/2) * W/nf * 0.29'" 
pd="'2*int((nf+1)/2) * (W/nf + 0.29)'"
as="'int((nf+2)/2) * W/nf * 0.29'" 
ps="'2*int((nf+2)/2) * (W/nf + 0.29)'"
nrd="'0.29 / W'" nrs="'0.29 / W'"
sa=0 sb=0 sd=0
model=nfet_01v8
spiceprefix=X
}
C {sky130_fd_pr/nfet_01v8.sym} -1360 -560 0 0 {name=MN7
*W=3
W = \{w_MN3\}
*L=0.5
L = \{l_MN3\}
nf=1
mult=1
ad="'int((nf+1)/2) * W/nf * 0.29'" 
pd="'2*int((nf+1)/2) * (W/nf + 0.29)'"
as="'int((nf+2)/2) * W/nf * 0.29'" 
ps="'2*int((nf+2)/2) * (W/nf + 0.29)'"
nrd="'0.29 / W'" nrs="'0.29 / W'"
sa=0 sb=0 sd=0
model=nfet_01v8
spiceprefix=X
}
C {sky130_fd_pr/nfet_01v8.sym} -1360 -670 0 0 {name=MN8
*W=2
W = \{w_MN4\}
*L=5
L = \{l_MN4\}
nf=1
mult=1
ad="'int((nf+1)/2) * W/nf * 0.29'" 
pd="'2*int((nf+1)/2) * (W/nf + 0.29)'"
as="'int((nf+2)/2) * W/nf * 0.29'" 
ps="'2*int((nf+2)/2) * (W/nf + 0.29)'"
nrd="'0.29 / W'" nrs="'0.29 / W'"
sa=0 sb=0 sd=0
model=nfet_01v8
spiceprefix=X
}
C {devices/lab_pin.sym} -1920 -890 0 0 {name=p25 sig_type=std_logic lab=VCONT}
C {devices/lab_pin.sym} -1780 -960 2 1 {name=p26 sig_type=std_logic lab=VCONT2}
C {devices/lab_pin.sym} -1280 -710 2 0 {name=p29 sig_type=std_logic lab=V_2}
C {devices/lab_pin.sym} -510 -960 1 0 {name=p31 sig_type=std_logic lab=VDD}
C {devices/lab_pin.sym} -510 -490 3 0 {name=p32 sig_type=std_logic lab=VSS}
C {sky130_fd_pr/pfet_01v8.sym} -1040 -890 0 0 {name=MP9
W= \{w_MP1a\}
L= \{l_MP1a\}
nf=1
mult=1
ad="'int((nf+1)/2) * W/nf * 0.29'" 
pd="'2*int((nf+1)/2) * (W/nf + 0.29)'"
as="'int((nf+2)/2) * W/nf * 0.29'" 
ps="'2*int((nf+2)/2) * (W/nf + 0.29)'"
nrd="'0.29 / W'" nrs="'0.29 / W'"
sa=0 sb=0 sd=0
model=pfet_01v8
spiceprefix=X
}
C {sky130_fd_pr/pfet_01v8.sym} -910 -890 0 0 {name=MP10
W=\{w_MP1b\}
*W=7
L=\{l_MP1b\}
nf=1
mult=1
ad="'int((nf+1)/2) * W/nf * 0.29'" 
pd="'2*int((nf+1)/2) * (W/nf + 0.29)'"
as="'int((nf+2)/2) * W/nf * 0.29'" 
ps="'2*int((nf+2)/2) * (W/nf + 0.29)'"
nrd="'0.29 / W'" nrs="'0.29 / W'"
sa=0 sb=0 sd=0
model=pfet_01v8
spiceprefix=X
}
C {sky130_fd_pr/pfet_01v8.sym} -740 -870 0 1 {name=MP11
*W= 8
W = \{w_MP2\}
*L= 4
L = \{l_MP2\}
nf=1
mult=1
ad="'int((nf+1)/2) * W/nf * 0.29'" 
pd="'2*int((nf+1)/2) * (W/nf + 0.29)'"
as="'int((nf+2)/2) * W/nf * 0.29'" 
ps="'2*int((nf+2)/2) * (W/nf + 0.29)'"
nrd="'0.29 / W'" nrs="'0.29 / W'"
sa=0 sb=0 sd=0
model=pfet_01v8
spiceprefix=X
}
C {sky130_fd_pr/pfet_01v8.sym} -530 -890 0 0 {name=MP12
*W=5
W = \{w_MP3\}
*L=4
L = \{l_MP3\}
nf=1
mult=1
ad="'int((nf+1)/2) * W/nf * 0.29'" 
pd="'2*int((nf+1)/2) * (W/nf + 0.29)'"
as="'int((nf+2)/2) * W/nf * 0.29'" 
ps="'2*int((nf+2)/2) * (W/nf + 0.29)'"
nrd="'0.29 / W'" nrs="'0.29 / W'"
sa=0 sb=0 sd=0
model=pfet_01v8
spiceprefix=X
}
C {sky130_fd_pr/pfet_01v8.sym} -530 -780 0 0 {name=MP13
*W=5
W = \{w_MP4\}
L = \{l_MP4\}
*L=5
nf=1
mult=1
ad="'int((nf+1)/2) * W/nf * 0.29'" 
pd="'2*int((nf+1)/2) * (W/nf + 0.29)'"
as="'int((nf+2)/2) * W/nf * 0.29'" 
ps="'2*int((nf+2)/2) * (W/nf + 0.29)'"
nrd="'0.29 / W'" nrs="'0.29 / W'"
sa=0 sb=0 sd=0
model=pfet_01v8
spiceprefix=X
}
C {sky130_fd_pr/nfet_01v8.sym} -1000 -560 0 1 {name=MN9
*W=5
W = \{w_MN1\}
*L=0.5
L = \{l_MN1\}
nf=1
mult=1
ad="'int((nf+1)/2) * W/nf * 0.29'" 
pd="'2*int((nf+1)/2) * (W/nf + 0.29)'"
as="'int((nf+2)/2) * W/nf * 0.29'" 
ps="'2*int((nf+2)/2) * (W/nf + 0.29)'"
nrd="'0.29 / W'" nrs="'0.29 / W'"
sa=0 sb=0 sd=0
model=nfet_01v8
spiceprefix=X
}
C {sky130_fd_pr/nfet_01v8.sym} -780 -560 0 0 {name=MN10
*W=5
W = \{w_MN2\}
*L=0.5
L = \{l_MN2\}
nf=1
mult=1
ad="'int((nf+1)/2) * W/nf * 0.29'" 
pd="'2*int((nf+1)/2) * (W/nf + 0.29)'"
as="'int((nf+2)/2) * W/nf * 0.29'" 
ps="'2*int((nf+2)/2) * (W/nf + 0.29)'"
nrd="'0.29 / W'" nrs="'0.29 / W'"
sa=0 sb=0 sd=0
model=nfet_01v8
spiceprefix=X
}
C {sky130_fd_pr/nfet_01v8.sym} -530 -560 0 0 {name=MN11
*W=3
W = \{w_MN3\}
*L=0.5
L = \{l_MN3\}
nf=1
mult=1
ad="'int((nf+1)/2) * W/nf * 0.29'" 
pd="'2*int((nf+1)/2) * (W/nf + 0.29)'"
as="'int((nf+2)/2) * W/nf * 0.29'" 
ps="'2*int((nf+2)/2) * (W/nf + 0.29)'"
nrd="'0.29 / W'" nrs="'0.29 / W'"
sa=0 sb=0 sd=0
model=nfet_01v8
spiceprefix=X
}
C {sky130_fd_pr/nfet_01v8.sym} -530 -670 0 0 {name=MN12
*W=2
W = \{w_MN4\}
*L=5
L = \{l_MN4\}
nf=1
mult=1
ad="'int((nf+1)/2) * W/nf * 0.29'" 
pd="'2*int((nf+1)/2) * (W/nf + 0.29)'"
as="'int((nf+2)/2) * W/nf * 0.29'" 
ps="'2*int((nf+2)/2) * (W/nf + 0.29)'"
nrd="'0.29 / W'" nrs="'0.29 / W'"
sa=0 sb=0 sd=0
model=nfet_01v8
spiceprefix=X
}
C {devices/lab_pin.sym} -1090 -890 0 0 {name=p33 sig_type=std_logic lab=VCONT}
C {devices/lab_pin.sym} -950 -960 2 1 {name=p34 sig_type=std_logic lab=VCONT2}
C {devices/lab_pin.sym} -450 -710 2 0 {name=p35 sig_type=std_logic lab=V_3}
C {devices/lab_pin.sym} 300 -970 1 0 {name=p37 sig_type=std_logic lab=VDD}
C {devices/lab_pin.sym} 300 -500 3 0 {name=p38 sig_type=std_logic lab=VSS}
C {sky130_fd_pr/pfet_01v8.sym} -230 -900 0 0 {name=MP14
W= \{w_MP1a\}
L= \{l_MP1a\}
nf=1
mult=1
ad="'int((nf+1)/2) * W/nf * 0.29'" 
pd="'2*int((nf+1)/2) * (W/nf + 0.29)'"
as="'int((nf+2)/2) * W/nf * 0.29'" 
ps="'2*int((nf+2)/2) * (W/nf + 0.29)'"
nrd="'0.29 / W'" nrs="'0.29 / W'"
sa=0 sb=0 sd=0
model=pfet_01v8
spiceprefix=X
}
C {sky130_fd_pr/pfet_01v8.sym} -100 -900 0 0 {name=MP15
W=\{w_MP1b\}
*W=7
L=\{l_MP1b\}
nf=1
mult=1
ad="'int((nf+1)/2) * W/nf * 0.29'" 
pd="'2*int((nf+1)/2) * (W/nf + 0.29)'"
as="'int((nf+2)/2) * W/nf * 0.29'" 
ps="'2*int((nf+2)/2) * (W/nf + 0.29)'"
nrd="'0.29 / W'" nrs="'0.29 / W'"
sa=0 sb=0 sd=0
model=pfet_01v8
spiceprefix=X
}
C {sky130_fd_pr/pfet_01v8.sym} 70 -880 0 1 {name=MP16
*W= 8
W = \{w_MP2\}
*L= 4
L = \{l_MP2\}
nf=1
mult=1
ad="'int((nf+1)/2) * W/nf * 0.29'" 
pd="'2*int((nf+1)/2) * (W/nf + 0.29)'"
as="'int((nf+2)/2) * W/nf * 0.29'" 
ps="'2*int((nf+2)/2) * (W/nf + 0.29)'"
nrd="'0.29 / W'" nrs="'0.29 / W'"
sa=0 sb=0 sd=0
model=pfet_01v8
spiceprefix=X
}
C {sky130_fd_pr/pfet_01v8.sym} 280 -900 0 0 {name=MP17
*W=5
W = \{w_MP3\}
*L=4
L = \{l_MP3\}
nf=1
mult=1
ad="'int((nf+1)/2) * W/nf * 0.29'" 
pd="'2*int((nf+1)/2) * (W/nf + 0.29)'"
as="'int((nf+2)/2) * W/nf * 0.29'" 
ps="'2*int((nf+2)/2) * (W/nf + 0.29)'"
nrd="'0.29 / W'" nrs="'0.29 / W'"
sa=0 sb=0 sd=0
model=pfet_01v8
spiceprefix=X
}
C {sky130_fd_pr/pfet_01v8.sym} 280 -790 0 0 {name=MP18
*W=5
W = \{w_MP4\}
L = \{l_MP4\}
*L=5
nf=1
mult=1
ad="'int((nf+1)/2) * W/nf * 0.29'" 
pd="'2*int((nf+1)/2) * (W/nf + 0.29)'"
as="'int((nf+2)/2) * W/nf * 0.29'" 
ps="'2*int((nf+2)/2) * (W/nf + 0.29)'"
nrd="'0.29 / W'" nrs="'0.29 / W'"
sa=0 sb=0 sd=0
model=pfet_01v8
spiceprefix=X
}
C {sky130_fd_pr/nfet_01v8.sym} -190 -570 0 1 {name=MN13
*W=5
W = \{w_MN1\}
*L=0.5
L = \{l_MN1\}
nf=1
mult=1
ad="'int((nf+1)/2) * W/nf * 0.29'" 
pd="'2*int((nf+1)/2) * (W/nf + 0.29)'"
as="'int((nf+2)/2) * W/nf * 0.29'" 
ps="'2*int((nf+2)/2) * (W/nf + 0.29)'"
nrd="'0.29 / W'" nrs="'0.29 / W'"
sa=0 sb=0 sd=0
model=nfet_01v8
spiceprefix=X
}
C {sky130_fd_pr/nfet_01v8.sym} 30 -570 0 0 {name=MN14
*W=5
W = \{w_MN2\}
*L=0.5
L = \{l_MN2\}
nf=1
mult=1
ad="'int((nf+1)/2) * W/nf * 0.29'" 
pd="'2*int((nf+1)/2) * (W/nf + 0.29)'"
as="'int((nf+2)/2) * W/nf * 0.29'" 
ps="'2*int((nf+2)/2) * (W/nf + 0.29)'"
nrd="'0.29 / W'" nrs="'0.29 / W'"
sa=0 sb=0 sd=0
model=nfet_01v8
spiceprefix=X
}
C {sky130_fd_pr/nfet_01v8.sym} 280 -570 0 0 {name=MN15
*W=3
W = \{w_MN3\}
*L=0.5
L = \{l_MN3\}
nf=1
mult=1
ad="'int((nf+1)/2) * W/nf * 0.29'" 
pd="'2*int((nf+1)/2) * (W/nf + 0.29)'"
as="'int((nf+2)/2) * W/nf * 0.29'" 
ps="'2*int((nf+2)/2) * (W/nf + 0.29)'"
nrd="'0.29 / W'" nrs="'0.29 / W'"
sa=0 sb=0 sd=0
model=nfet_01v8
spiceprefix=X
}
C {sky130_fd_pr/nfet_01v8.sym} 280 -680 0 0 {name=MN16
*W=2
W = \{w_MN4\}
*L=5
L = \{l_MN4\}
nf=1
mult=1
ad="'int((nf+1)/2) * W/nf * 0.29'" 
pd="'2*int((nf+1)/2) * (W/nf + 0.29)'"
as="'int((nf+2)/2) * W/nf * 0.29'" 
ps="'2*int((nf+2)/2) * (W/nf + 0.29)'"
nrd="'0.29 / W'" nrs="'0.29 / W'"
sa=0 sb=0 sd=0
model=nfet_01v8
spiceprefix=X
}
C {devices/lab_pin.sym} -280 -900 0 0 {name=p39 sig_type=std_logic lab=VCONT}
C {devices/lab_pin.sym} -140 -970 2 1 {name=p40 sig_type=std_logic lab=VCONT2}
C {devices/lab_pin.sym} 360 -720 2 0 {name=p41 sig_type=std_logic lab=V_4}
C {devices/lab_pin.sym} 1120 -970 1 0 {name=p43 sig_type=std_logic lab=VDD}
C {devices/lab_pin.sym} 1120 -500 3 0 {name=p44 sig_type=std_logic lab=VSS}
C {sky130_fd_pr/pfet_01v8.sym} 590 -900 0 0 {name=MP19
W= \{w_MP1a\}
L= \{l_MP1a\}
nf=1
mult=1
ad="'int((nf+1)/2) * W/nf * 0.29'" 
pd="'2*int((nf+1)/2) * (W/nf + 0.29)'"
as="'int((nf+2)/2) * W/nf * 0.29'" 
ps="'2*int((nf+2)/2) * (W/nf + 0.29)'"
nrd="'0.29 / W'" nrs="'0.29 / W'"
sa=0 sb=0 sd=0
model=pfet_01v8
spiceprefix=X
}
C {sky130_fd_pr/pfet_01v8.sym} 720 -900 0 0 {name=MP20
W=\{w_MP1b\}
*W=7
L=\{l_MP1b\}
nf=1
mult=1
ad="'int((nf+1)/2) * W/nf * 0.29'" 
pd="'2*int((nf+1)/2) * (W/nf + 0.29)'"
as="'int((nf+2)/2) * W/nf * 0.29'" 
ps="'2*int((nf+2)/2) * (W/nf + 0.29)'"
nrd="'0.29 / W'" nrs="'0.29 / W'"
sa=0 sb=0 sd=0
model=pfet_01v8
spiceprefix=X
}
C {sky130_fd_pr/pfet_01v8.sym} 890 -880 0 1 {name=MP21
*W= 8
W = \{w_MP2\}
*L= 4
L = \{l_MP2\}
nf=1
mult=1
ad="'int((nf+1)/2) * W/nf * 0.29'" 
pd="'2*int((nf+1)/2) * (W/nf + 0.29)'"
as="'int((nf+2)/2) * W/nf * 0.29'" 
ps="'2*int((nf+2)/2) * (W/nf + 0.29)'"
nrd="'0.29 / W'" nrs="'0.29 / W'"
sa=0 sb=0 sd=0
model=pfet_01v8
spiceprefix=X
}
C {sky130_fd_pr/pfet_01v8.sym} 1100 -900 0 0 {name=MP22
*W=5
W = \{w_MP3\}
*L=4
L = \{l_MP3\}
nf=1
mult=1
ad="'int((nf+1)/2) * W/nf * 0.29'" 
pd="'2*int((nf+1)/2) * (W/nf + 0.29)'"
as="'int((nf+2)/2) * W/nf * 0.29'" 
ps="'2*int((nf+2)/2) * (W/nf + 0.29)'"
nrd="'0.29 / W'" nrs="'0.29 / W'"
sa=0 sb=0 sd=0
model=pfet_01v8
spiceprefix=X
}
C {sky130_fd_pr/pfet_01v8.sym} 1100 -790 0 0 {name=MP23
*W=5
W = \{w_MP4\}
L = \{l_MP4\}
*L=5
nf=1
mult=1
ad="'int((nf+1)/2) * W/nf * 0.29'" 
pd="'2*int((nf+1)/2) * (W/nf + 0.29)'"
as="'int((nf+2)/2) * W/nf * 0.29'" 
ps="'2*int((nf+2)/2) * (W/nf + 0.29)'"
nrd="'0.29 / W'" nrs="'0.29 / W'"
sa=0 sb=0 sd=0
model=pfet_01v8
spiceprefix=X
}
C {sky130_fd_pr/nfet_01v8.sym} 630 -570 0 1 {name=MN17
*W=5
W = \{w_MN1\}
*L=0.5
L = \{l_MN1\}
nf=1
mult=1
ad="'int((nf+1)/2) * W/nf * 0.29'" 
pd="'2*int((nf+1)/2) * (W/nf + 0.29)'"
as="'int((nf+2)/2) * W/nf * 0.29'" 
ps="'2*int((nf+2)/2) * (W/nf + 0.29)'"
nrd="'0.29 / W'" nrs="'0.29 / W'"
sa=0 sb=0 sd=0
model=nfet_01v8
spiceprefix=X
}
C {sky130_fd_pr/nfet_01v8.sym} 850 -570 0 0 {name=MN18
*W=5
W = \{w_MN2\}
*L=0.5
L = \{l_MN2\}
nf=1
mult=1
ad="'int((nf+1)/2) * W/nf * 0.29'" 
pd="'2*int((nf+1)/2) * (W/nf + 0.29)'"
as="'int((nf+2)/2) * W/nf * 0.29'" 
ps="'2*int((nf+2)/2) * (W/nf + 0.29)'"
nrd="'0.29 / W'" nrs="'0.29 / W'"
sa=0 sb=0 sd=0
model=nfet_01v8
spiceprefix=X
}
C {sky130_fd_pr/nfet_01v8.sym} 1100 -570 0 0 {name=MN19
*W=3
W = \{w_MN3\}
*L=0.5
L = \{l_MN3\}
nf=1
mult=1
ad="'int((nf+1)/2) * W/nf * 0.29'" 
pd="'2*int((nf+1)/2) * (W/nf + 0.29)'"
as="'int((nf+2)/2) * W/nf * 0.29'" 
ps="'2*int((nf+2)/2) * (W/nf + 0.29)'"
nrd="'0.29 / W'" nrs="'0.29 / W'"
sa=0 sb=0 sd=0
model=nfet_01v8
spiceprefix=X
}
C {sky130_fd_pr/nfet_01v8.sym} 1100 -680 0 0 {name=MN20
*W=2
W = \{w_MN4\}
*L=5
L = \{l_MN4\}
nf=1
mult=1
ad="'int((nf+1)/2) * W/nf * 0.29'" 
pd="'2*int((nf+1)/2) * (W/nf + 0.29)'"
as="'int((nf+2)/2) * W/nf * 0.29'" 
ps="'2*int((nf+2)/2) * (W/nf + 0.29)'"
nrd="'0.29 / W'" nrs="'0.29 / W'"
sa=0 sb=0 sd=0
model=nfet_01v8
spiceprefix=X
}
C {devices/lab_pin.sym} 540 -900 0 0 {name=p45 sig_type=std_logic lab=VCONT}
C {devices/lab_pin.sym} 680 -970 2 1 {name=p46 sig_type=std_logic lab=VCONT2}
C {devices/lab_pin.sym} 1180 -720 2 0 {name=p47 sig_type=std_logic lab=V_5}
